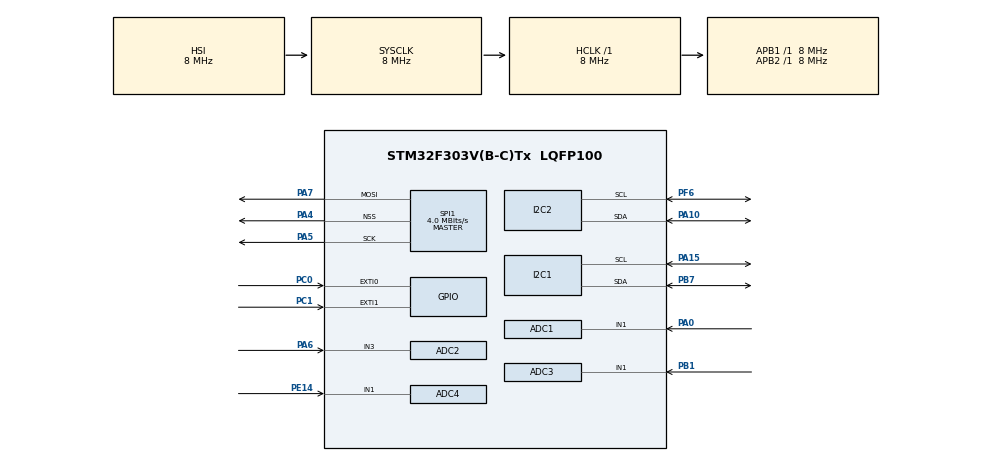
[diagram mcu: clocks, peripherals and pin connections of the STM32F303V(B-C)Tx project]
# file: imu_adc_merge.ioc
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ADC1.Channel-0\#ChannelRegularConversion=ADC_CHANNEL_1
ADC1.NbrOfConversionFlag=1
ADC1.Offset-0\#ChannelRegularConversion=0
ADC1.OffsetNumber-0\#ChannelRegularConversion=ADC_OFFSET_NONE
ADC1.Rank-0\#ChannelRegularConversion=1
ADC1.SamplingTime-0\#ChannelRegularConversion=ADC_SAMPLETIME_1CYCLE_5
ADC1.SamplingTimeOPAMP-0\#ChannelRegularConversion=ADC_SAMPLETIME_4CYCLES_5
ADC1.master=1
ADC2.Channel-0\#ChannelRegularConversion=ADC_CHANNEL_3
ADC2.NbrOfConversionFlag=1
ADC2.Offset-0\#ChannelRegularConversion=0
ADC2.OffsetNumber-0\#ChannelRegularConversion=ADC_OFFSET_NONE
ADC2.Rank-0\#ChannelRegularConversion=1
ADC2.SamplingTime-0\#ChannelRegularConversion=ADC_SAMPLETIME_1CYCLE_5
ADC2.SamplingTimeOPAMP-0\#ChannelRegularConversion=ADC_SAMPLETIME_4CYCLES_5
ADC3.Channel-0\#ChannelRegularConversion=ADC_CHANNEL_1
ADC3.NbrOfConversionFlag=1
ADC3.Offset-0\#ChannelRegularConversion=0
ADC3.OffsetNumber-0\#ChannelRegularConversion=ADC_OFFSET_NONE
ADC3.Rank-0\#ChannelRegularConversion=1
ADC3.SamplingTime-0\#ChannelRegularConversion=ADC_SAMPLETIME_1CYCLE_5
ADC3.master=1
ADC4.Channel-0\#ChannelRegularConversion=ADC_CHANNEL_1
ADC4.NbrOfConversionFlag=1
ADC4.Offset-0\#ChannelRegularConversion=0
ADC4.OffsetNumber-0\#ChannelRegularConversion=ADC_OFFSET_NONE
ADC4.Rank-0\#ChannelRegularConversion=1
ADC4.SamplingTime-0\#ChannelRegularConversion=ADC_SAMPLETIME_1CYCLE_5
ADC4.SamplingTimeOPAMP-0\#ChannelRegularConversion=ADC_SAMPLETIME_4CYCLES_5
Dma.Request0=SPI1_TX
Dma.SPI1_TX.0.Direction=DMA_MEMORY_TO_PERIPH
Dma.SPI1_TX.0.Instance=DMA1_Channel3
Dma.SPI1_TX.0.MemDataAlignment=DMA_MDATAALIGN_BYTE
Dma.SPI1_TX.0.MemInc=DMA_MINC_ENABLE
Dma.SPI1_TX.0.Mode=DMA_NORMAL
Dma.SPI1_TX.0.PeriphDataAlignment=DMA_PDATAALIGN_BYTE
Dma.SPI1_TX.0.PeriphInc=DMA_PINC_DISABLE
Dma.SPI1_TX.0.Priority=DMA_PRIORITY_LOW
Mcu.Family=STM32F3
Mcu.Name=STM32F303V(B-C)Tx
Mcu.Package=LQFP100
NVIC.DMA1_Channel3_IRQn=true\:0\:0\:false\:false\:true\:false\:true\:true
NVIC.EXTI0_IRQn=true\:0\:0\:false\:false\:true\:true\:true\:true
NVIC.EXTI1_IRQn=true\:0\:0\:false\:false\:true\:true\:true\:true
NVIC.I2C1_EV_IRQn=true\:0\:0\:false\:false\:true\:true\:true\:true
NVIC.I2C2_EV_IRQn=true\:0\:0\:false\:false\:true\:true\:true\:true
NVIC.PriorityGroup=NVIC_PRIORITYGROUP_4
NVIC.TIM1_UP_TIM16_IRQn=true\:0\:0\:false\:false\:true\:true\:true\:true
PA0.Mode=IN1-Single-Ended
PA0.Signal=ADC1_IN1
PA10.Mode=I2C
PA10.Signal=I2C2_SDA
PA13.Mode=Serial_Wire
PA13.Signal=SYS_JTMS-SWDIO
PA14.Mode=Serial_Wire
PA14.Signal=SYS_JTCK-SWCLK
PA15.Mode=I2C
PA15.Signal=I2C1_SCL
PA4.Mode=NSS_Signal_Hard_Output
PA4.Signal=SPI1_NSS
PA5.Mode=TX_Only_Simplex_Unidirect_Master
PA5.Signal=SPI1_SCK
PA6.Mode=IN3-Single-Ended
PA6.Signal=ADC2_IN3
PA7.Mode=TX_Only_Simplex_Unidirect_Master
PA7.Signal=SPI1_MOSI
PB1.Mode=IN1-Single-Ended
PB1.Signal=ADC3_IN1
PB7.Mode=I2C
PB7.Signal=I2C1_SDA
PC0.GPIO_ModeDefaultEXTI=GPIO_MODE_IT_RISING
PC0.GPIO_PuPd=GPIO_PULLDOWN
PC0.Signal=GPXTI0
PC1.GPIO_PuPd=GPIO_PULLDOWN
PC1.Signal=GPXTI1
PE14.Mode=IN1-Single-Ended
PE14.Signal=ADC4_IN1
PF0-OSC_IN.Mode=HSE-External-Oscillator
PF0-OSC_IN.Signal=RCC_OSC_IN
PF1-OSC_OUT.Mode=HSE-External-Oscillator
PF1-OSC_OUT.Signal=RCC_OSC_OUT
PF6.Mode=I2C
PF6.Signal=I2C2_SCL
ProjectManager.HeapSize=0x200
ProjectManager.StackSize=0x400
ProjectManager.TargetToolchain=STM32CubeIDE
RCC.AHBFreq_Value=8000000
RCC.APB1Freq_Value=8000000
RCC.APB2Freq_Value=8000000
RCC.CortexFreq_Value=8000000
RCC.HSE_VALUE=8000000
RCC.HSI_VALUE=8000000
RCC.LSE_VALUE=32768
RCC.PLLMUL=RCC_PLL_MUL4
RCC.SYSCLKFreq_VALUE=8000000
RCC.USBFreq_Value=16000000
SPI1.CalculateBaudRate=4.0 MBits/s
SPI1.Direction=SPI_DIRECTION_2LINES
SPI1.Mode=SPI_MODE_MASTER
SPI1.VirtualNSS=VM_NSSHARD
SPI1.VirtualType=VM_MASTER
TIM16.Period=10000 - 1
TIM16.Prescaler=8000 - 1
VP_TIM16_VS_ClockSourceINT.Mode=Enable_Timer
board=custom

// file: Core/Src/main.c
/* USER CODE BEGIN Header */
/**
  ******************************************************************************
  * @file           : main.c
  * @brief          : Main program body
  ******************************************************************************
  * @attention
  *
  * Copyright (c) 2023 STMicroelectronics.
  * All rights reserved.
  *
  * This software is licensed under terms that can be found in the LICENSE file
  * in the root directory of this software component.
  * If no LICENSE file comes with this software, it is provided AS-IS.
  *
  ******************************************************************************
  */
/* USER CODE END Header */
#include "main.h"

/* USER CODE BEGIN Includes */
#include "adc_setup.c"
#include "imu_setup.c"
#include "dac_setup.h"
#include "lcd_setup.h"
#include "calculate_orientation.h"
#include "calculate_gestures.h"
#include "utils.h"
#include <float.h>

/* USER CODE END Includes */

ADC_HandleTypeDef hadc1;
ADC_HandleTypeDef hadc2;
ADC_HandleTypeDef hadc3;
ADC_HandleTypeDef hadc4;

I2C_HandleTypeDef hi2c1;
I2C_HandleTypeDef hi2c2;

SPI_HandleTypeDef hspi1;
DMA_HandleTypeDef hdma_spi1_tx;

TIM_HandleTypeDef htim16;

/* USER CODE BEGIN PV */

volatile float q0 = 1.0f, q1 = 0.0f, q2 = 0.0f, q3 = 0.0f;  // quaternion of sensor frame relative to auxiliary frame
volatile float angle_x = 0.0f, angle_y = 0.0f, angle_z = 0.0f;
volatile float gimbal_roll = 0.0f;
volatile float gimbal_pitch = 0.0f;
volatile float gimbal_yaw = 0.0f;
volatile float gimbal_throttle = 0.0f;

sensors_event_t gyro;
sensors_event_t accel;
sensors_event_t mag;

int ADC_vals[4];
float resistance_min[4];
float resistance_max[4];

stmdev_ctx_t dev_ctx_imu;
stmdev_ctx_t dev_ctx_mag;

extern dacChannelConfig config;
extern dacChannelConfig output;
extern dacChannelConfig channels;

int t1 = 0, t2 = 0;
float delay;

float voltage_vals[4] = {1.64, 1.57, 0.1, 1.79};
int DAC_resting[4] = {0, 0, 0, 0};
int DAC_factor[4] = {3000, 3000, 1500, 1500};

states state = INIT;
int did_state_change;

int cnt_sec;

DispState currDisp;

/* USER CODE END PV */

void SystemClock_Config(void);
static void MX_GPIO_Init(void);
static void MX_DMA_Init(void);
static void MX_ADC1_Init(void);
static void MX_ADC2_Init(void);
static void MX_ADC3_Init(void);
static void MX_ADC4_Init(void);
static void MX_I2C1_Init(void);
static void MX_I2C2_Init(void);
static void MX_TIM16_Init(void);
static void MX_SPI1_Init(void);

void Set_AdvancedMode(int start_adv);
void Set_StandardMode(void);
void Start_AdvancedMode(void);

void HAL_GPIO_EXTI_Callback(uint16_t GPIO_Pin) {
    if (GPIO_Pin == GPIO_PIN_0) {
		if (HAL_GPIO_ReadPin(GPIOC, GPIO_PIN_0) == GPIO_PIN_SET) {
			Set_AdvancedMode(1);
		}
    } else if (GPIO_Pin == GPIO_PIN_1) {
    	if (HAL_GPIO_ReadPin(GPIOC, GPIO_PIN_1) == GPIO_PIN_SET) {
    		Set_StandardMode();
    	}
    }
//    exti_test1 = HAL_GPIO_ReadPin(GPIOC, GPIO_PIN_0);
//    exti_test2 = HAL_GPIO_ReadPin(GPIOC, GPIO_PIN_1);
}

void Set_AdvancedMode(int start_adv) {
	state = MODE_ADVANCED;
  if (start_adv == 1) {
	  Start_AdvancedMode();
  }
}
void Set_StandardMode() {
	state = MODE_STANDARD;
}

// Callback: timer has rolled over
void HAL_TIM_PeriodElapsedCallback(TIM_HandleTypeDef *htim) {
  if (htim == &htim16) {
  did_state_change = 0;
	if (state == INIT) { // State: INIT
		if (cnt_sec <= 0) {
			calibrate_init();
			state = CAL_UNFLEXED;
			cnt_sec = CAL_TIME_SEC;
      did_state_change = 1;
		} else {
			cnt_sec -= 1;
		}
	} else if (state == CAL_UNFLEXED) { // State: CAL_UNFLEXED
      ADC_Read();
	  for (int i = 0; i < 4; i++) {
      resistance_max[i] = max(resistance_max[i], calculate_finger_resistance(i));
	  }
      if (cnt_sec <= 0) {
        state = CAL_FLEXED;
        cnt_sec = CAL_TIME_SEC;
        did_state_change = 1;
      } else {
        cnt_sec -= 1;
      }
    } else if (state == CAL_FLEXED) { // State: CAL_FLEXED
      ADC_Read();
      for (int i = 0; i < 4; i++) {
    		resistance_min[i] = min(resistance_min[i], calculate_finger_resistance(i));
      }
      if (cnt_sec <= 0) {
    	int is_resistance_range_valid = 1;
    	for (int i = 0; i < 4; i++) {
    		if (resistance_max[i] - resistance_min[i] < RESISTANCE_RANGE_THRESH) {
    			is_resistance_range_valid = 0;
    			break;
    		}
    	}
    	if (is_resistance_range_valid != 0) {
//    		HAL_TIM_Base_Stop_IT(&htim16);
      htim16.Init.Period = 1000 - 1;
			HAL_NVIC_EnableIRQ(EXTI0_IRQn);
			HAL_NVIC_EnableIRQ(EXTI1_IRQn);
			if (HAL_GPIO_ReadPin(GPIOC, GPIO_PIN_0) == GPIO_PIN_SET) { // @henry: check PC0 IDR for starting mode
        Set_AdvancedMode(0);
			} else {
	      Set_StandardMode();
			}
			LCD_DrawFillRectangle(CAL_CIRCLE_X - 8, CAL_CIRCLE_Y - 8, CAL_CIRCLE_X + 8, CAL_CIRCLE_Y + 8, BLACK); // hides countdown from calibration stages
    	} else {
    		state = CAL_UNFLEXED;
    		cnt_sec = CAL_TIME_SEC;
    	}
      did_state_change = 1;
      } else {
        cnt_sec -= 1;
      }
    }
  LCD_update(gimbal_roll, gimbal_pitch, gimbal_throttle, gimbal_yaw, state, CAL_TIME_SEC, cnt_sec);
  }
}

int main(void)
{

  /* MCU Configuration--------------------------------------------------------*/

  /* Reset of all peripherals, Initializes the Flash interface and the Systick. */
  HAL_Init();

  /* Configure the system clock */
  SystemClock_Config();

  /* Initialize all configured peripherals */
  MX_GPIO_Init();
  MX_DMA_Init();
  MX_ADC1_Init();
  MX_ADC2_Init();
  MX_ADC3_Init();
  MX_ADC4_Init();
  MX_I2C1_Init();
  MX_I2C2_Init();
  MX_TIM16_Init();
  MX_SPI1_Init();
//  SPI1_Setup();
  LCD_Init(0,0,0);
  LCD_Clear(BLACK);

  /* USER CODE BEGIN 2 */
  if (IMU_Setup() != SETUP_SUCCESS) {
	  return 1;
  }
  MCP4728_Init(&hi2c2, output);
  output.channelVref = 0x00;
  output.channel_Gain = 0x00;
  convert_voltage_to_ADC(voltage_vals);
  output.channel_Val[0] = DAC_resting[0]; // pitch
  output.channel_Val[1] = DAC_resting[1]; // roll
  output.channel_Val[2] = DAC_resting[2]; // throttle
  output.channel_Val[3] = DAC_resting[3]; // yaw

  state = INIT;
  cnt_sec = INIT_TIME_SEC;
  HAL_TIM_Base_Start_IT(&htim16); // @henry: starting timer
//  state = MODE_ADVANCED;
//  Start_AdvancedMode();
  /* USER CODE END 2 */

  while (1);
}

int convert_voltage_to_ADC(float* voltage_vals) {
	for (int i = 0; i < 4; i++) {
		DAC_resting[i] = voltage_vals[i] * ((2 << ADC_NUM_BITS - 1) - 1) / VCC;
	}
}

void Start_AdvancedMode(void) {
  reset_aux_frame();
  t1 = HAL_GetTick();

  /* Infinite loop */
  /* USER CODE BEGIN WHILE */
  while (state == MODE_ADVANCED) {
	  /* SENSOR READ BEGIN */
	  ADC_Read();
	  IMU_Read();

	  /* SENSOR READ END */

	  /* CALCULATIONS BEGIN */
	  t2 = HAL_GetTick();
//	  calculate_orientation((t2 - t1) / 1000.0f); // @henry: adaptive frequency was way too fast
	  calculate_orientation(0.02);
	  t1 = t2;
	  calculate_gestures();

	  /* CALCULATIONS END*/

	  /* OUTPUT BEGIN */
	  output.channel_Val[0] = DAC_resting[0] + (gimbal_pitch - 0.5) * DAC_factor[0]; // pitch
	  output.channel_Val[1] = DAC_resting[1] + (gimbal_roll - 0.5) * DAC_factor[1]; // roll
	  output.channel_Val[2] = DAC_resting[2] + (gimbal_throttle * 2) * DAC_factor[2]; // throttle
	  output.channel_Val[3] = DAC_resting[3] + (gimbal_yaw - 0.5) * DAC_factor[3]; // yaw
	  MCP4728_Write_AllChannels_Diff(&hi2c2, output);

	  /* OUTPUT END */
  }
}

void SystemClock_Config(void)
{
  RCC_OscInitTypeDef RCC_OscInitStruct = {0};
  RCC_ClkInitTypeDef RCC_ClkInitStruct = {0};
  RCC_PeriphCLKInitTypeDef PeriphClkInit = {0};

  /** Initializes the RCC Oscillators according to the specified parameters
  * in the RCC_OscInitTypeDef structure.
  */
  RCC_OscInitStruct.OscillatorType = RCC_OSCILLATORTYPE_HSI;
  RCC_OscInitStruct.HSIState = RCC_HSI_ON;
  RCC_OscInitStruct.HSICalibrationValue = RCC_HSICALIBRATION_DEFAULT;
  RCC_OscInitStruct.PLL.PLLState = RCC_PLL_ON;
  RCC_OscInitStruct.PLL.PLLSource = RCC_PLLSOURCE_HSI;
  RCC_OscInitStruct.PLL.PLLMUL = RCC_PLL_MUL4;
  if (HAL_RCC_OscConfig(&RCC_OscInitStruct) != HAL_OK)
  {
    Error_Handler();
  }

  /** Initializes the CPU, AHB and APB buses clocks
  */
  RCC_ClkInitStruct.ClockType = RCC_CLOCKTYPE_HCLK|RCC_CLOCKTYPE_SYSCLK
                              |RCC_CLOCKTYPE_PCLK1|RCC_CLOCKTYPE_PCLK2;
  RCC_ClkInitStruct.SYSCLKSource = RCC_SYSCLKSOURCE_HSI;
  RCC_ClkInitStruct.AHBCLKDivider = RCC_SYSCLK_DIV1;
  RCC_ClkInitStruct.APB1CLKDivider = RCC_HCLK_DIV1;
  RCC_ClkInitStruct.APB2CLKDivider = RCC_HCLK_DIV1;

  if (HAL_RCC_ClockConfig(&RCC_ClkInitStruct, FLASH_LATENCY_0) != HAL_OK)
  {
    Error_Handler();
  }
  PeriphClkInit.PeriphClockSelection = RCC_PERIPHCLK_I2C1|RCC_PERIPHCLK_I2C2
                              |RCC_PERIPHCLK_ADC12|RCC_PERIPHCLK_ADC34;
  PeriphClkInit.Adc12ClockSelection = RCC_ADC12PLLCLK_DIV1;
  PeriphClkInit.Adc34ClockSelection = RCC_ADC34PLLCLK_DIV1;
  PeriphClkInit.I2c1ClockSelection = RCC_I2C1CLKSOURCE_HSI;
  PeriphClkInit.I2c2ClockSelection = RCC_I2C2CLKSOURCE_HSI;
  if (HAL_RCCEx_PeriphCLKConfig(&PeriphClkInit) != HAL_OK)
  {
    Error_Handler();
  }
}

static void MX_ADC1_Init(void)
{

  ADC_MultiModeTypeDef multimode = {0};
  ADC_ChannelConfTypeDef sConfig = {0};

  /** Common config
  */
  hadc1.Instance = ADC1;
  hadc1.Init.ClockPrescaler = ADC_CLOCK_ASYNC_DIV1;
  hadc1.Init.Resolution = ADC_RESOLUTION_12B;
  hadc1.Init.ScanConvMode = ADC_SCAN_DISABLE;
  hadc1.Init.ContinuousConvMode = DISABLE;
  hadc1.Init.DiscontinuousConvMode = DISABLE;
  hadc1.Init.ExternalTrigConvEdge = ADC_EXTERNALTRIGCONVEDGE_NONE;
  hadc1.Init.ExternalTrigConv = ADC_SOFTWARE_START;
  hadc1.Init.DataAlign = ADC_DATAALIGN_RIGHT;
  hadc1.Init.NbrOfConversion = 1;
  hadc1.Init.DMAContinuousRequests = DISABLE;
  hadc1.Init.EOCSelection = ADC_EOC_SINGLE_CONV;
  hadc1.Init.LowPowerAutoWait = DISABLE;
  hadc1.Init.Overrun = ADC_OVR_DATA_OVERWRITTEN;
  if (HAL_ADC_Init(&hadc1) != HAL_OK)
  {
    Error_Handler();
  }

  /** Configure the ADC multi-mode
  */
  multimode.Mode = ADC_MODE_INDEPENDENT;
  if (HAL_ADCEx_MultiModeConfigChannel(&hadc1, &multimode) != HAL_OK)
  {
    Error_Handler();
  }

  /** Configure Regular Channel
  */
  sConfig.Channel = ADC_CHANNEL_1;
  sConfig.Rank = ADC_REGULAR_RANK_1;
  sConfig.SingleDiff = ADC_SINGLE_ENDED;
  sConfig.SamplingTime = ADC_SAMPLETIME_1CYCLE_5;
  sConfig.OffsetNumber = ADC_OFFSET_NONE;
  sConfig.Offset = 0;
  if (HAL_ADC_ConfigChannel(&hadc1, &sConfig) != HAL_OK)
  {
    Error_Handler();
  }
  /* USER CODE BEGIN ADC1_Init 2 */
  ADC_Calibrate(ADC1);
//  ADC_ADVREGEN(ADC1); // @henry
//  ADC12_COMMON->CCR|= ADC_CCR_VREFEN; // @henry

  ADC1->CR |= ADC_CR_ADEN; // Enable ADC
//  while ((ADC1->ISR & ADC_ISR_ADRDY) == 0); // Wait for ADC to be ready

  ADC1->CFGR |= ADC_CFGR_CONT; //Continuous Conversion Mode
  ADC1->CFGR &= ~0xC; // 12-bit Resolution

  ADC1->SQR1 &= ~0xF; // 1 conversion in regular channel conversion sequence
  ADC1->SQR1 |= 0x1 << 6; // Channel 1 of ADC1

  while ((ADC1->ISR & ADC_ISR_ADRDY) == 0); // Wait for ADC to be ready
  ADC1->CR |= ADC_CR_ADSTART; // Start the ADC
  /* USER CODE END ADC1_Init 2 */

}

static void MX_ADC2_Init(void)
{

  ADC_ChannelConfTypeDef sConfig = {0};

  /** Common config
  */
  hadc2.Instance = ADC2;
  hadc2.Init.ClockPrescaler = ADC_CLOCK_ASYNC_DIV1;
  hadc2.Init.Resolution = ADC_RESOLUTION_12B;
  hadc2.Init.ScanConvMode = ADC_SCAN_DISABLE;
  hadc2.Init.ContinuousConvMode = DISABLE;
  hadc2.Init.DiscontinuousConvMode = DISABLE;
  hadc2.Init.ExternalTrigConvEdge = ADC_EXTERNALTRIGCONVEDGE_NONE;
  hadc2.Init.ExternalTrigConv = ADC_SOFTWARE_START;
  hadc2.Init.DataAlign = ADC_DATAALIGN_RIGHT;
  hadc2.Init.NbrOfConversion = 1;
  hadc2.Init.DMAContinuousRequests = DISABLE;
  hadc2.Init.EOCSelection = ADC_EOC_SINGLE_CONV;
  hadc2.Init.LowPowerAutoWait = DISABLE;
  hadc2.Init.Overrun = ADC_OVR_DATA_OVERWRITTEN;
  if (HAL_ADC_Init(&hadc2) != HAL_OK)
  {
    Error_Handler();
  }

  /** Configure Regular Channel
  */
  sConfig.Channel = ADC_CHANNEL_3;
  sConfig.Rank = ADC_REGULAR_RANK_1;
  sConfig.SingleDiff = ADC_SINGLE_ENDED;
  sConfig.SamplingTime = ADC_SAMPLETIME_1CYCLE_5;
  sConfig.OffsetNumber = ADC_OFFSET_NONE;
  sConfig.Offset = 0;
  if (HAL_ADC_ConfigChannel(&hadc2, &sConfig) != HAL_OK)
  {
    Error_Handler();
  }
  /* USER CODE BEGIN ADC2_Init 2 */
  ADC_Calibrate(ADC2);

  ADC2->CR |= ADC_CR_ADEN; // Enable ADC
//  while ((ADC2->ISR & ADC_ISR_ADRDY) == 0); // Wait for ADC to be ready

  ADC2->CFGR |= ADC_CFGR_CONT; //Continuous Conversion Mode
  ADC2->CFGR &= ~0xC; // 12-bit Resolution

  ADC2->SQR1 &= ~0xF; // 1 conversion in regular channel conversion sequence
  ADC2->SQR1 |= 0x3 << 6; // Channel 3 of ADC2

  while ((ADC2->ISR & ADC_ISR_ADRDY) == 0); // Wait for ADC to be ready
  ADC2->CR |= ADC_CR_ADSTART; // Start the ADC
  /* USER CODE END ADC2_Init 2 */

}

static void MX_ADC3_Init(void)
{

  ADC_MultiModeTypeDef multimode = {0};
  ADC_ChannelConfTypeDef sConfig = {0};

  /** Common config
  */
  hadc3.Instance = ADC3;
  hadc3.Init.ClockPrescaler = ADC_CLOCK_ASYNC_DIV1;
  hadc3.Init.Resolution = ADC_RESOLUTION_12B;
  hadc3.Init.ScanConvMode = ADC_SCAN_DISABLE;
  hadc3.Init.ContinuousConvMode = DISABLE;
  hadc3.Init.DiscontinuousConvMode = DISABLE;
  hadc3.Init.ExternalTrigConvEdge = ADC_EXTERNALTRIGCONVEDGE_NONE;
  hadc3.Init.ExternalTrigConv = ADC_SOFTWARE_START;
  hadc3.Init.DataAlign = ADC_DATAALIGN_RIGHT;
  hadc3.Init.NbrOfConversion = 1;
  hadc3.Init.DMAContinuousRequests = DISABLE;
  hadc3.Init.EOCSelection = ADC_EOC_SINGLE_CONV;
  hadc3.Init.LowPowerAutoWait = DISABLE;
  hadc3.Init.Overrun = ADC_OVR_DATA_OVERWRITTEN;
  if (HAL_ADC_Init(&hadc3) != HAL_OK)
  {
    Error_Handler();
  }

  /** Configure the ADC multi-mode
  */
  multimode.Mode = ADC_MODE_INDEPENDENT;
  if (HAL_ADCEx_MultiModeConfigChannel(&hadc3, &multimode) != HAL_OK)
  {
    Error_Handler();
  }

  /** Configure Regular Channel
  */
  sConfig.Channel = ADC_CHANNEL_1;
  sConfig.Rank = ADC_REGULAR_RANK_1;
  sConfig.SingleDiff = ADC_SINGLE_ENDED;
  sConfig.SamplingTime = ADC_SAMPLETIME_1CYCLE_5;
  sConfig.OffsetNumber = ADC_OFFSET_NONE;
  sConfig.Offset = 0;
  if (HAL_ADC_ConfigChannel(&hadc3, &sConfig) != HAL_OK)
  {
    Error_Handler();
  }
  /* USER CODE BEGIN ADC3_Init 2 */
  ADC_Calibrate(ADC3);

  ADC3->CR |= ADC_CR_ADEN; // Enable ADC
//  while ((ADC3->ISR & ADC_ISR_ADRDY) == 0); // Wait for ADC to be ready

  ADC3->CFGR |= ADC_CFGR_CONT; //Continuous Conversion Mode
  ADC3->CFGR &= ~0xC; // 12-bit Resolution

  ADC3->SQR1 &= ~0xF; // 1 conversion in regular channel conversion sequence
  ADC3->SQR1 |= 0x1 << 6; // Channel 1 of ADC3

  while ((ADC3->ISR & ADC_ISR_ADRDY) == 0); // Wait for ADC to be ready
  ADC3->CR |= ADC_CR_ADSTART; // Start the ADC
  /* USER CODE END ADC3_Init 2 */

}

static void MX_ADC4_Init(void)
{

  ADC_ChannelConfTypeDef sConfig = {0};

  /** Common config
  */
  hadc4.Instance = ADC4;
  hadc4.Init.ClockPrescaler = ADC_CLOCK_ASYNC_DIV1;
  hadc4.Init.Resolution = ADC_RESOLUTION_12B;
  hadc4.Init.ScanConvMode = ADC_SCAN_DISABLE;
  hadc4.Init.ContinuousConvMode = DISABLE;
  hadc4.Init.DiscontinuousConvMode = DISABLE;
  hadc4.Init.ExternalTrigConvEdge = ADC_EXTERNALTRIGCONVEDGE_NONE;
  hadc4.Init.ExternalTrigConv = ADC_SOFTWARE_START;
  hadc4.Init.DataAlign = ADC_DATAALIGN_RIGHT;
  hadc4.Init.NbrOfConversion = 1;
  hadc4.Init.DMAContinuousRequests = DISABLE;
  hadc4.Init.EOCSelection = ADC_EOC_SINGLE_CONV;
  hadc4.Init.LowPowerAutoWait = DISABLE;
  hadc4.Init.Overrun = ADC_OVR_DATA_OVERWRITTEN;
  if (HAL_ADC_Init(&hadc4) != HAL_OK)
  {
    Error_Handler();
  }

  /** Configure Regular Channel
  */
  sConfig.Channel = ADC_CHANNEL_1;
  sConfig.Rank = ADC_REGULAR_RANK_1;
  sConfig.SingleDiff = ADC_SINGLE_ENDED;
  sConfig.SamplingTime = ADC_SAMPLETIME_1CYCLE_5;
  sConfig.OffsetNumber = ADC_OFFSET_NONE;
  sConfig.Offset = 0;
  if (HAL_ADC_ConfigChannel(&hadc4, &sConfig) != HAL_OK)
  {
    Error_Handler();
  }
  /* USER CODE BEGIN ADC4_Init 2 */
  ADC_Calibrate(ADC4);

  ADC4->CR |= ADC_CR_ADEN; // Enable ADC
//  while ((ADC4->ISR & ADC_ISR_ADRDY) == 0); // Wait for ADC to be ready

  ADC4->CFGR |= ADC_CFGR_CONT; //Continuous Conversion Mode
  ADC4->CFGR &= ~0xC; // 12-bit Resolution

  ADC4->SQR1 &= ~0xF; // 1 conversion in regular channel conversion sequence
  ADC4->SQR1 |= 0x1 << 6; // Channel 1 of ADC4

  while ((ADC4->ISR & ADC_ISR_ADRDY) == 0); // Wait for ADC to be ready
  ADC4->CR |= ADC_CR_ADSTART; // Start the ADC
  /* USER CODE END ADC4_Init 2 */

}

static void MX_I2C1_Init(void)
{

  hi2c1.Instance = I2C1;
  hi2c1.Init.Timing = 0x2000090E;
  hi2c1.Init.OwnAddress1 = 0;
  hi2c1.Init.AddressingMode = I2C_ADDRESSINGMODE_7BIT;
  hi2c1.Init.DualAddressMode = I2C_DUALADDRESS_DISABLE;
  hi2c1.Init.OwnAddress2 = 0;
  hi2c1.Init.OwnAddress2Masks = I2C_OA2_NOMASK;
  hi2c1.Init.GeneralCallMode = I2C_GENERALCALL_DISABLE;
  hi2c1.Init.NoStretchMode = I2C_NOSTRETCH_DISABLE;
  if (HAL_I2C_Init(&hi2c1) != HAL_OK)
  {
    Error_Handler();
  }

  /** Configure Analogue filter
  */
  if (HAL_I2CEx_ConfigAnalogFilter(&hi2c1, I2C_ANALOGFILTER_ENABLE) != HAL_OK)
  {
    Error_Handler();
  }

  /** Configure Digital filter
  */
  if (HAL_I2CEx_ConfigDigitalFilter(&hi2c1, 0) != HAL_OK)
  {
    Error_Handler();
  }

}

static void MX_I2C2_Init(void)
{

  hi2c2.Instance = I2C2;
  hi2c2.Init.Timing = 0x2000090E;
  hi2c2.Init.OwnAddress1 = 0;
  hi2c2.Init.AddressingMode = I2C_ADDRESSINGMODE_7BIT;
  hi2c2.Init.DualAddressMode = I2C_DUALADDRESS_DISABLE;
  hi2c2.Init.OwnAddress2 = 0;
  hi2c2.Init.OwnAddress2Masks = I2C_OA2_NOMASK;
  hi2c2.Init.GeneralCallMode = I2C_GENERALCALL_DISABLE;
  hi2c2.Init.NoStretchMode = I2C_NOSTRETCH_DISABLE;
  if (HAL_I2C_Init(&hi2c2) != HAL_OK)
  {
    Error_Handler();
  }

  /** Configure Analogue filter
  */
  if (HAL_I2CEx_ConfigAnalogFilter(&hi2c2, I2C_ANALOGFILTER_ENABLE) != HAL_OK)
  {
    Error_Handler();
  }

  /** Configure Digital filter
  */
  if (HAL_I2CEx_ConfigDigitalFilter(&hi2c2, 0) != HAL_OK)
  {
    Error_Handler();
  }

}

static void MX_SPI1_Init(void)
{
	/* SPI1 parameter configuration*/
	hspi1.Instance = SPI1;
	hspi1.Init.Mode = SPI_MODE_MASTER;
	hspi1.Init.Direction = SPI_DIRECTION_2LINES;
	hspi1.Init.DataSize = SPI_DATASIZE_4BIT;
	hspi1.Init.CLKPolarity = SPI_POLARITY_LOW;
	hspi1.Init.CLKPhase = SPI_PHASE_1EDGE;
	hspi1.Init.NSS = SPI_NSS_HARD_OUTPUT;
	hspi1.Init.BaudRatePrescaler = SPI_BAUDRATEPRESCALER_4;
	hspi1.Init.FirstBit = SPI_FIRSTBIT_MSB;
	hspi1.Init.TIMode = SPI_TIMODE_DISABLE;
	hspi1.Init.CRCCalculation = SPI_CRCCALCULATION_DISABLE;
	hspi1.Init.CRCPolynomial = 7;
	hspi1.Init.CRCLength = SPI_CRC_LENGTH_DATASIZE;
	hspi1.Init.NSSPMode = SPI_NSS_PULSE_ENABLE;
	if (HAL_SPI_Init(&hspi1) != HAL_OK)
	{
	Error_Handler();
	}
	GPIOB->ODR |= 0x1;
	GPIOA->ODR |= 0x18;

	RCC->APB2ENR |= RCC_APB2ENR_SPI1EN;
	SPI1->CR2 &= ~SPI_CR2_DS;
	SPI1->CR1 &= ~(SPI_CR1_BR);
	SPI1->CR1 |= SPI_CR1_MSTR;
	SPI1->CR1 |= SPI_CR1_SSM | SPI_CR1_SSI;
	SPI1->CR1 |= SPI_CR1_SPE;
}

static void MX_TIM16_Init(void)
{
	htim16.Instance = TIM16;
	htim16.Init.Prescaler = 8000 - 1;
	htim16.Init.CounterMode = TIM_COUNTERMODE_UP;
	htim16.Init.Period = 1000 - 1;
	htim16.Init.ClockDivision = TIM_CLOCKDIVISION_DIV1;
	htim16.Init.RepetitionCounter = 0;
	htim16.Init.AutoReloadPreload = TIM_AUTORELOAD_PRELOAD_DISABLE;
	if (HAL_TIM_Base_Init(&htim16) != HAL_OK)
	{
	Error_Handler();
	}
}

static void MX_DMA_Init(void)
{
	/* DMA controller clock enable */
	__HAL_RCC_DMA1_CLK_ENABLE();
	/* DMA interrupt init */
	/* DMA1_Channel3_IRQn interrupt configuration */
	HAL_NVIC_SetPriority(DMA1_Channel3_IRQn, 0, 0);
	HAL_NVIC_EnableIRQ(DMA1_Channel3_IRQn);
}

static void MX_GPIO_Init(void)
{
  GPIO_InitTypeDef GPIO_InitStruct = {0};

  /* GPIO Ports Clock Enable */
  __HAL_RCC_GPIOA_CLK_ENABLE();
  __HAL_RCC_GPIOB_CLK_ENABLE();
  __HAL_RCC_GPIOC_CLK_ENABLE();
  __HAL_RCC_GPIOE_CLK_ENABLE();
  __HAL_RCC_GPIOF_CLK_ENABLE();

  /*Configure GPIO pin Output Level */
  HAL_GPIO_WritePin(GPIOA, GPIO_PIN_3, GPIO_PIN_RESET);

  /*Configure GPIO pin Output Level */
  HAL_GPIO_WritePin(GPIOB, GPIO_PIN_0, GPIO_PIN_RESET);

  /*Configure GPIO pin : PA3 */
  GPIO_InitStruct.Pin = GPIO_PIN_3;
  GPIO_InitStruct.Mode = GPIO_MODE_OUTPUT_PP;
  GPIO_InitStruct.Pull = GPIO_NOPULL;
  GPIO_InitStruct.Speed = GPIO_SPEED_FREQ_LOW;
  HAL_GPIO_Init(GPIOA, &GPIO_InitStruct);

  /*Configure GPIO pin : PB0 */
  GPIO_InitStruct.Pin = GPIO_PIN_0;
  GPIO_InitStruct.Mode = GPIO_MODE_OUTPUT_PP;
  GPIO_InitStruct.Pull = GPIO_NOPULL;
  GPIO_InitStruct.Speed = GPIO_SPEED_FREQ_LOW;
  HAL_GPIO_Init(GPIOB, &GPIO_InitStruct);

  /*Configure GPIO pins : PC0 PC1 */
  GPIO_InitStruct.Pin = GPIO_PIN_0|GPIO_PIN_1;
  GPIO_InitStruct.Mode = GPIO_MODE_IT_RISING;
  GPIO_InitStruct.Pull = GPIO_PULLDOWN;
  HAL_GPIO_Init(GPIOC, &GPIO_InitStruct);
  /* EXTI interrupt init*/
  HAL_NVIC_SetPriority(EXTI0_IRQn, 1, 0);
//  HAL_NVIC_EnableIRQ(EXTI0_IRQn);

  HAL_NVIC_SetPriority(EXTI1_IRQn, 0, 0);
//  HAL_NVIC_EnableIRQ(EXTI1_IRQn);

}

void Error_Handler(void)
{
  __disable_irq();
  while (1)
  {
  }
}
